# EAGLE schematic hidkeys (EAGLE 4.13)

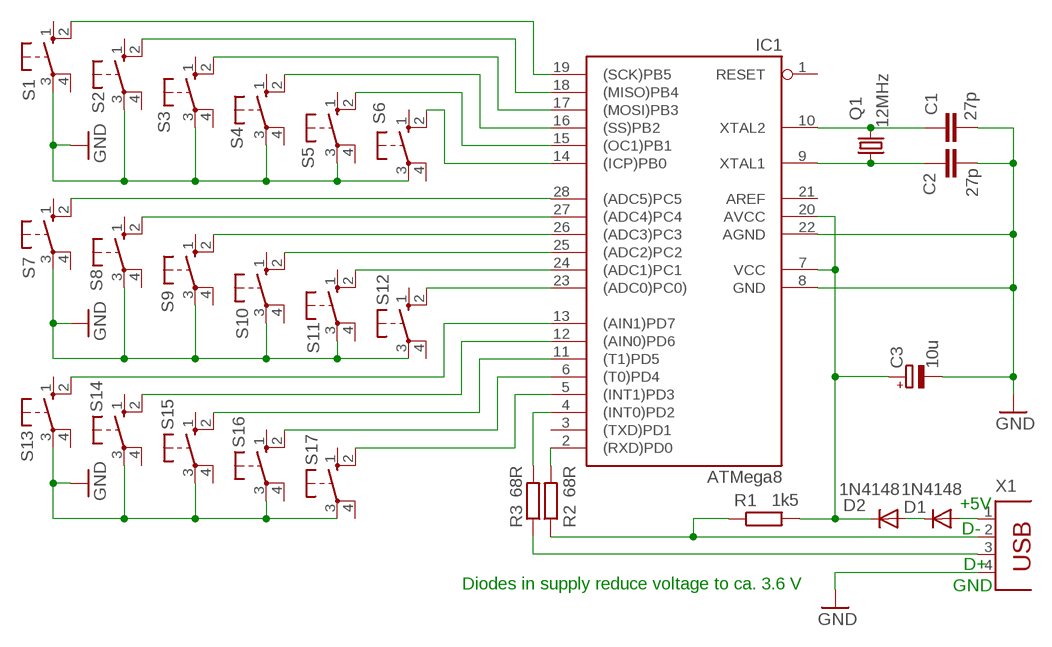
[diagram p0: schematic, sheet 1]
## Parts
C1  27p  C-EU025-024X044  [C025-024X044]
C2  27p  C-EU025-024X044  [C025-024X044]
C3  10u  CPOL-EUE2.5-5  [E2,5-5]
D1  1N4148  [DO35-10]
D2  1N4148  [DO35-10]
IC1  ATMega8  AT90S4433P  [DIL28-3]
Q1  12MHz  CRYTALHC49S  [HC49/S]
R1  1k5  R-EU_0207/7  [0207/7]
R2  68R  R-EU_0207/7  [0207/7]
R3  68R  R-EU_0207/7  [0207/7]
S1  10-XX  [B3F-10XX]
S2  10-XX  [B3F-10XX]
S3  10-XX  [B3F-10XX]
S4  10-XX  [B3F-10XX]
S5  10-XX  [B3F-10XX]
S6  10-XX  [B3F-10XX]
S7  10-XX  [B3F-10XX]
S8  10-XX  [B3F-10XX]
S9  10-XX  [B3F-10XX]
S10  10-XX  [B3F-10XX]
S11  10-XX  [B3F-10XX]
S12  10-XX  [B3F-10XX]
S13  10-XX  [B3F-10XX]
S14  10-XX  [B3F-10XX]
S15  10-XX  [B3F-10XX]
S16  10-XX  [B3F-10XX]
S17  10-XX  [B3F-10XX]
X1  PN61729  [PN61729]

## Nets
GND: C1.2 C2.2 C3.- IC1.8(GND) IC1.22(AGND) S1.3(P) S2.3(P) S3.3(P) S4.3(P) S5.3(P) S6.3(P) S7.3(P) S8.3(P) S9.3(P) S10.3(P) S11.3(P) S12.3(P) S13.3(P) S14.3(P) S15.3(P) S16.3(P) S17.3(P) X1.4
N$1: IC1.19((SCK)PB5) S1.2(S1)
N$2: IC1.18((MISO)PB4) S2.2(S1)
N$3: IC1.17((MOSI)PB3) S3.2(S1)
N$4: IC1.16((SS)PB2) S4.2(S1)
N$5: IC1.15((OC1)PB1) S5.2(S1)
N$6: IC1.14((ICP)PB0) S6.2(S1)
N$7: IC1.28((ADC5)PC5) S7.2(S1)
N$8: IC1.27((ADC4)PC4) S8.2(S1)
N$9: IC1.26((ADC3)PC3) S9.2(S1)
N$10: IC1.25((ADC2)PC2) S10.2(S1)
N$11: IC1.24((ADC1)PC1) S11.2(S1)
N$12: IC1.23((ADC0)PC0)) S12.2(S1)
N$13: IC1.13((AIN1)PD7) S13.2(S1)
N$14: IC1.12((AIN0)PD6) S14.2(S1)
N$15: IC1.11((T1)PD5) S15.2(S1)
N$16: IC1.6((T0)PD4) S16.2(S1)
N$17: IC1.5((INT1)PD3) S17.2(S1)
N$18: R1.1 R2.1 X1.2
N$19: R3.1 X1.3
N$20: IC1.4((INT0)PD2) R3.2
N$21: C1.1 IC1.10(XTAL2) Q1.2
N$22: C2.1 IC1.9(XTAL1) Q1.1
N$23: IC1.2((RXD)PD0) R2.2
N$24: D1.A X1.1
N$25: D1.C D2.A
VCC: C3.+ D2.C IC1.7(VCC) IC1.20(AVCC) R1.2
Unconnected: IC1.1(RESET) IC1.3((TXD)PD1) S1.1(S) S1.4(P1) S2.1(S) S2.4(P1) S3.1(S) S3.4(P1) S4.1(S) S4.4(P1) S5.1(S) S5.4(P1) S6.1(S) S6.4(P1) S7.1(S) S7.4(P1) S8.1(S) S8.4(P1) S9.1(S) S9.4(P1) S10.1(S) S10.4(P1) S11.1(S) S11.4(P1) S12.1(S) S12.4(P1) S13.1(S) S13.4(P1) S14.1(S) S14.4(P1) S15.1(S) S15.4(P1) S16.1(S) S16.4(P1) S17.1(S) S17.4(P1)

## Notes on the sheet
- +5V
- D-
- D+
- Diodes in supply reduce voltage to ca. 3.6 V | GND

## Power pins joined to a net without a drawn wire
AREF: IC1.21(AREF)

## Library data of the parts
C1 C2 = rcl:C-EU: CAPACITOR, European symbol
C3 = rcl:CPOL-EU: POLARIZED CAPACITOR, European symbol
D1 D2 = diode:1N4148: DIODE
IC1 = atmel:AT90S4433: MICROCONTROLLER 4 Kbytes FLASH 128 bytes SRAM 256 bytes EEPROM UART 6-channel 10 bit ADC
Q1 = crystal:CRYTAL: CRYSTAL
R1-R3 = rcl:R-EU_: RESISTOR, European symbol
S1-S17 = switch-omron:10-XX: OMRON SWITCH
X1 = con-berg:PN61729: BERG USB connector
